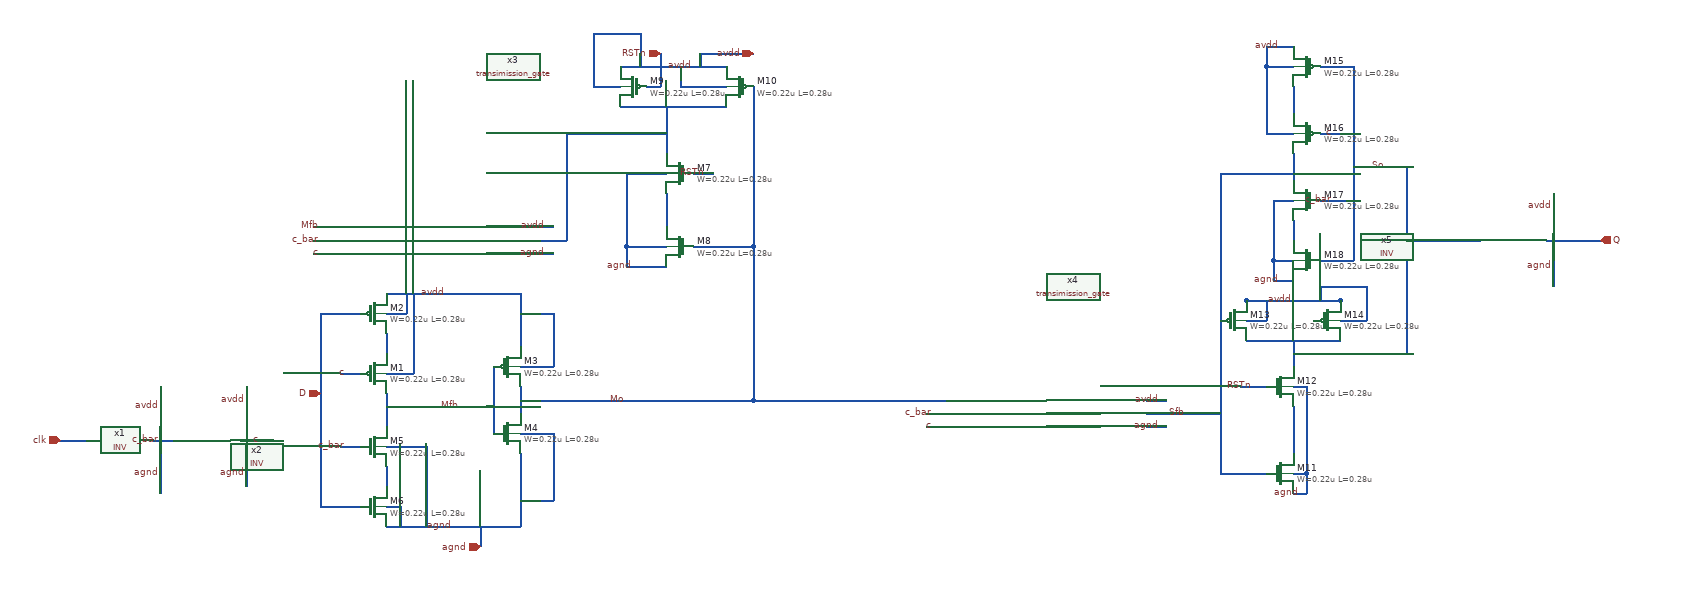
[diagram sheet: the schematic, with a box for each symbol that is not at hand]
v {xschem version=3.1.0 file_version=1.2
}
G {}
K {}
V {}
S {}
E {}
N 1270 -210 1320 -210 {
lab=c}
N 1000 -210 1040 -210 {
lab=clk}
N 1140 -210 1170 -210 {
lab=c_bar}
N 1490 -370 1490 -340 {
lab=#net1}
N 1490 -280 1490 -230 {
lab=Mfb}
N 1490 -170 1490 -140 {
lab=#net2}
N 1690 -290 1690 -250 {
lab=Mo}
N 1690 -190 1690 -80 {
lab=agnd}
N 1490 -80 1690 -80 {
lab=agnd}
N 1490 -430 1690 -430 {
lab=avdd}
N 1690 -430 1690 -350 {
lab=avdd}
N 1390 -400 1450 -400 {
lab=D}
N 1390 -400 1390 -110 {
lab=D}
N 1390 -110 1450 -110 {
lab=D}
N 1650 -320 1650 -220 {
lab=Mfb}
N 1490 -260 1650 -260 {
lab=Mfb}
N 1420 -310 1450 -310 {
lab=c}
N 1420 -200 1450 -200 {
lab=c_bar}
N 1490 -110 1510 -110 {
lab=agnd}
N 1510 -110 1510 -80 {
lab=agnd}
N 1490 -200 1550 -200 {
lab=agnd}
N 1550 -200 1550 -80 {
lab=agnd}
N 1690 -220 1740 -220 {
lab=agnd}
N 1740 -220 1740 -120 {
lab=agnd}
N 1690 -120 1740 -120 {
lab=agnd}
N 1690 -320 1740 -320 {
lab=avdd}
N 1740 -400 1740 -320 {
lab=avdd}
N 1690 -400 1740 -400 {
lab=avdd}
N 1380 -530 1410 -530 {
lab=Mfb}
N 1380 -510 1410 -510 {
lab=c_bar}
N 1380 -490 1410 -490 {
lab=c}
N 1710 -530 1740 -530 {
lab=avdd}
N 1710 -510 1740 -510 {
lab=#net3}
N 1710 -490 1740 -490 {
lab=agnd}
N 1910 -580 1910 -530 {
lab=#net4}
N 1850 -610 1910 -610 {
lab=agnd}
N 1850 -610 1850 -500 {
lab=agnd}
N 1850 -500 1910 -500 {
lab=agnd}
N 1850 -470 1910 -470 {
lab=agnd}
N 1850 -500 1850 -470 {
lab=agnd}
N 1840 -710 2000 -710 {
lab=#net3}
N 1910 -710 1910 -640 {
lab=#net3}
N 2040 -740 2040 -500 {
lab=Mo}
N 1950 -500 2040 -500 {
lab=Mo}
N 1950 -610 1980 -610 {
lab=RSTn}
N 1840 -770 2000 -770 {
lab=avdd}
N 1880 -740 1900 -740 {
lab=RSTn}
N 1900 -790 1900 -740 {
lab=RSTn}
N 1800 -740 1840 -740 {
lab=avdd}
N 1800 -820 1800 -740 {
lab=avdd}
N 1800 -820 1870 -820 {
lab=avdd}
N 1870 -820 1870 -770 {
lab=avdd}
N 1930 -740 2000 -740 {
lab=avdd}
N 1930 -770 1930 -740 {
lab=avdd}
N 1760 -670 1910 -670 {
lab=#net3}
N 1760 -670 1760 -510 {
lab=#net3}
N 1740 -510 1760 -510 {
lab=#net3}
N 2040 -500 2040 -290 {
lab=Mo}
N 1690 -270 2040 -270 {
lab=Mo}
N 2040 -290 2040 -270 {
lab=Mo}
N 2300 -270 2330 -270 {
lab=Mo}
N 2300 -250 2330 -250 {
lab=c_bar}
N 2300 -230 2330 -230 {
lab=c}
N 2630 -270 2660 -270 {
lab=avdd}
N 2630 -250 2660 -250 {
lab=Sfb}
N 2630 -230 2660 -230 {
lab=agnd}
N 2040 -270 2300 -270 {
lab=Mo}
N 2780 -420 2920 -420 {
lab=avdd}
N 2780 -360 2920 -360 {
lab=So}
N 2850 -360 2850 -320 {
lab=So}
N 2850 -260 2850 -190 {
lab=#net5}
N 2850 -290 2870 -290 {
lab=agnd}
N 2870 -290 2870 -160 {
lab=agnd}
N 2850 -160 2870 -160 {
lab=agnd}
N 2870 -160 2870 -130 {
lab=agnd}
N 2850 -130 2870 -130 {
lab=agnd}
N 2750 -160 2810 -160 {
lab=Sfb}
N 2740 -160 2750 -160 {
lab=Sfb}
N 2740 -390 2740 -160 {
lab=Sfb}
N 2660 -250 2740 -250 {
lab=Sfb}
N 2770 -290 2810 -290 {
lab=RSTn}
N 2920 -390 2960 -390 {
lab=avdd}
N 2960 -440 2960 -390 {
lab=avdd}
N 2890 -440 2960 -440 {
lab=avdd}
N 2890 -440 2890 -420 {
lab=avdd}
N 2780 -390 2810 -390 {
lab=avdd}
N 2810 -420 2810 -390 {
lab=avdd}
N 2820 -480 2850 -480 {
lab=agnd}
N 2820 -480 2820 -450 {
lab=agnd}
N 2820 -450 2850 -450 {
lab=agnd}
N 2820 -570 2850 -570 {
lab=agnd}
N 2820 -570 2820 -480 {
lab=agnd}
N 2850 -540 2850 -510 {
lab=#net6}
N 2850 -640 2850 -600 {
lab=Sfb}
N 2850 -740 2850 -700 {
lab=#net7}
N 2810 -670 2850 -670 {
lab=avdd}
N 2810 -770 2810 -670 {
lab=avdd}
N 2810 -770 2850 -770 {
lab=avdd}
N 2810 -800 2850 -800 {
lab=avdd}
N 2810 -800 2810 -770 {
lab=avdd}
N 2740 -610 2850 -610 {
lab=Sfb}
N 2740 -610 2740 -390 {
lab=Sfb}
N 2890 -770 2940 -770 {
lab=So}
N 2940 -770 2940 -480 {
lab=So}
N 2890 -480 2940 -480 {
lab=So}
N 2890 -670 2920 -670 {
lab=c}
N 2890 -570 2930 -570 {
lab=c_bar}
N 2850 -340 3020 -340 {
lab=So}
N 3020 -620 3020 -340 {
lab=So}
N 2940 -620 3020 -620 {
lab=So}
N 2780 -420 2920 -420 {
lab=avdd}
N 2780 -420 2920 -420 {
lab=avdd}
N 3020 -510 3130 -510 {
lab=So}
N 3230 -510 3310 -510 {
lab=Q}
N 1960 -790 2040 -790 {
lab=avdd}
N 1960 -790 1960 -770 {
lab=avdd}
N 1630 -80 1630 -50 {
lab=agnd}
N 1490 -400 1520 -400 {
lab=avdd}
N 1520 -430 1520 -400 {
lab=avdd}
N 1490 -310 1530 -310 {
lab=avdd}
N 1530 -430 1530 -310 {
lab=avdd}
N 3240 -580 3240 -530 {
lab=avdd}
N 3240 -490 3240 -440 {
lab=agnd}
N 1150 -290 1150 -230 {
lab=avdd}
N 1150 -190 1150 -130 {
lab=agnd}
N 1280 -290 1280 -230 {
lab=avdd}
N 1280 -190 1280 -140 {
lab=xxx}
C {INV.sym} 1100 -210 0 0 {name=x1}
C {INV.sym} 1230 -210 0 0 {name=x2}
C {pfet_03v3.sym} 1470 -310 0 0 {name=M1
L=0.28u
W=0.22u
nf=1
m=1
ad="'int((nf+1)/2) * W/nf * 0.18u'"
pd="'2*int((nf+1)/2) * (W/nf + 0.18u)'"
as="'int((nf+2)/2) * W/nf * 0.18u'"
ps="'2*int((nf+2)/2) * (W/nf + 0.18u)'"
nrd="'0.18u / W'" nrs="'0.18u / W'"
sa=0 sb=0 sd=0
model=pfet_03v3
spiceprefix=X
}
C {pfet_03v3.sym} 1470 -400 0 0 {name=M2
L=0.28u
W=0.22u
nf=1
m=1
ad="'int((nf+1)/2) * W/nf * 0.18u'"
pd="'2*int((nf+1)/2) * (W/nf + 0.18u)'"
as="'int((nf+2)/2) * W/nf * 0.18u'"
ps="'2*int((nf+2)/2) * (W/nf + 0.18u)'"
nrd="'0.18u / W'" nrs="'0.18u / W'"
sa=0 sb=0 sd=0
model=pfet_03v3
spiceprefix=X
}
C {pfet_03v3.sym} 1670 -320 0 0 {name=M3
L=0.28u
W=0.22u
nf=1
m=1
ad="'int((nf+1)/2) * W/nf * 0.18u'"
pd="'2*int((nf+1)/2) * (W/nf + 0.18u)'"
as="'int((nf+2)/2) * W/nf * 0.18u'"
ps="'2*int((nf+2)/2) * (W/nf + 0.18u)'"
nrd="'0.18u / W'" nrs="'0.18u / W'"
sa=0 sb=0 sd=0
model=pfet_03v3
spiceprefix=X
}
C {nfet_03v3.sym} 1670 -220 0 0 {name=M4
L=0.28u
W=0.22u
nf=1
m=1
ad="'int((nf+1)/2) * W/nf * 0.18u'"
pd="'2*int((nf+1)/2) * (W/nf + 0.18u)'"
as="'int((nf+2)/2) * W/nf * 0.18u'"
ps="'2*int((nf+2)/2) * (W/nf + 0.18u)'"
nrd="'0.18u / W'" nrs="'0.18u / W'"
sa=0 sb=0 sd=0
model=nfet_03v3
spiceprefix=X
}
C {nfet_03v3.sym} 1470 -200 0 0 {name=M5
L=0.28u
W=0.22u
nf=1
m=1
ad="'int((nf+1)/2) * W/nf * 0.18u'"
pd="'2*int((nf+1)/2) * (W/nf + 0.18u)'"
as="'int((nf+2)/2) * W/nf * 0.18u'"
ps="'2*int((nf+2)/2) * (W/nf + 0.18u)'"
nrd="'0.18u / W'" nrs="'0.18u / W'"
sa=0 sb=0 sd=0
model=nfet_03v3
spiceprefix=X
}
C {nfet_03v3.sym} 1470 -110 0 0 {name=M6
L=0.28u
W=0.22u
nf=1
m=1
ad="'int((nf+1)/2) * W/nf * 0.18u'"
pd="'2*int((nf+1)/2) * (W/nf + 0.18u)'"
as="'int((nf+2)/2) * W/nf * 0.18u'"
ps="'2*int((nf+2)/2) * (W/nf + 0.18u)'"
nrd="'0.18u / W'" nrs="'0.18u / W'"
sa=0 sb=0 sd=0
model=nfet_03v3
spiceprefix=X
}
C {lab_pin.sym} 1590 -80 0 0 {name=p1 sig_type=std_logic lab=agnd}
C {lab_pin.sym} 1580 -430 0 0 {name=p2 sig_type=std_logic lab=avdd}
C {lab_pin.sym} 1430 -310 0 0 {name=p3 sig_type=std_logic lab=c}
C {lab_pin.sym} 1430 -200 0 0 {name=p4 sig_type=std_logic lab=c_bar}
C {ipin.sym} 1000 -210 0 0 {name=p5 lab=clk}
C {lab_pin.sym} 1150 -210 0 0 {name=p6 sig_type=std_logic lab=c_bar}
C {lab_pin.sym} 1300 -210 0 0 {name=p7 sig_type=std_logic lab=c}
C {lab_pin.sym} 1600 -260 0 0 {name=p8 sig_type=std_logic lab=Mfb}
C {transimission_gate.sym} 1560 -510 0 0 {name=x3}
C {lab_pin.sym} 1730 -530 0 0 {name=p9 sig_type=std_logic lab=avdd}
C {lab_pin.sym} 1730 -490 0 0 {name=p10 sig_type=std_logic lab=agnd}
C {lab_pin.sym} 1390 -530 0 0 {name=p11 sig_type=std_logic lab=Mfb}
C {lab_pin.sym} 1390 -510 0 0 {name=p12 sig_type=std_logic lab=c_bar}
C {lab_pin.sym} 1390 -490 0 0 {name=p13 sig_type=std_logic lab=c}
C {nfet_03v3.sym} 1930 -610 0 1 {name=M7
L=0.28u
W=0.22u
nf=1
m=1
ad="'int((nf+1)/2) * W/nf * 0.18u'"
pd="'2*int((nf+1)/2) * (W/nf + 0.18u)'"
as="'int((nf+2)/2) * W/nf * 0.18u'"
ps="'2*int((nf+2)/2) * (W/nf + 0.18u)'"
nrd="'0.18u / W'" nrs="'0.18u / W'"
sa=0 sb=0 sd=0
model=nfet_03v3
spiceprefix=X
}
C {nfet_03v3.sym} 1930 -500 0 1 {name=M8
L=0.28u
W=0.22u
nf=1
m=1
ad="'int((nf+1)/2) * W/nf * 0.18u'"
pd="'2*int((nf+1)/2) * (W/nf + 0.18u)'"
as="'int((nf+2)/2) * W/nf * 0.18u'"
ps="'2*int((nf+2)/2) * (W/nf + 0.18u)'"
nrd="'0.18u / W'" nrs="'0.18u / W'"
sa=0 sb=0 sd=0
model=nfet_03v3
spiceprefix=X
}
C {pfet_03v3.sym} 1860 -740 0 1 {name=M9
L=0.28u
W=0.22u
nf=1
m=1
ad="'int((nf+1)/2) * W/nf * 0.18u'"
pd="'2*int((nf+1)/2) * (W/nf + 0.18u)'"
as="'int((nf+2)/2) * W/nf * 0.18u'"
ps="'2*int((nf+2)/2) * (W/nf + 0.18u)'"
nrd="'0.18u / W'" nrs="'0.18u / W'"
sa=0 sb=0 sd=0
model=pfet_03v3
spiceprefix=X
}
C {pfet_03v3.sym} 2020 -740 0 1 {name=M10
L=0.28u
W=0.22u
nf=1
m=1
ad="'int((nf+1)/2) * W/nf * 0.18u'"
pd="'2*int((nf+1)/2) * (W/nf + 0.18u)'"
as="'int((nf+2)/2) * W/nf * 0.18u'"
ps="'2*int((nf+2)/2) * (W/nf + 0.18u)'"
nrd="'0.18u / W'" nrs="'0.18u / W'"
sa=0 sb=0 sd=0
model=pfet_03v3
spiceprefix=X
}
C {lab_pin.sym} 1970 -610 0 0 {name=p14 sig_type=std_logic lab=RSTn}
C {ipin.sym} 1900 -790 0 0 {name=p15 lab=RSTn}
C {lab_pin.sym} 1950 -770 0 0 {name=p16 sig_type=std_logic lab=avdd}
C {lab_pin.sym} 1860 -470 0 0 {name=p17 sig_type=std_logic lab=agnd}
C {transimission_gate.sym} 2480 -250 0 0 {name=x4}
C {lab_pin.sym} 2650 -270 0 0 {name=p18 sig_type=std_logic lab=avdd}
C {lab_pin.sym} 2650 -230 0 0 {name=p19 sig_type=std_logic lab=agnd}
C {lab_pin.sym} 2310 -250 0 0 {name=p21 sig_type=std_logic lab=c_bar}
C {lab_pin.sym} 2310 -230 0 0 {name=p22 sig_type=std_logic lab=c}
C {lab_pin.sym} 1850 -270 0 0 {name=p20 sig_type=std_logic lab=Mo}
C {nfet_03v3.sym} 2830 -160 0 0 {name=M11
L=0.28u
W=0.22u
nf=1
m=1
ad="'int((nf+1)/2) * W/nf * 0.18u'"
pd="'2*int((nf+1)/2) * (W/nf + 0.18u)'"
as="'int((nf+2)/2) * W/nf * 0.18u'"
ps="'2*int((nf+2)/2) * (W/nf + 0.18u)'"
nrd="'0.18u / W'" nrs="'0.18u / W'"
sa=0 sb=0 sd=0
model=nfet_03v3
spiceprefix=X
}
C {nfet_03v3.sym} 2830 -290 0 0 {name=M12
L=0.28u
W=0.22u
nf=1
m=1
ad="'int((nf+1)/2) * W/nf * 0.18u'"
pd="'2*int((nf+1)/2) * (W/nf + 0.18u)'"
as="'int((nf+2)/2) * W/nf * 0.18u'"
ps="'2*int((nf+2)/2) * (W/nf + 0.18u)'"
nrd="'0.18u / W'" nrs="'0.18u / W'"
sa=0 sb=0 sd=0
model=nfet_03v3
spiceprefix=X
}
C {pfet_03v3.sym} 2760 -390 0 0 {name=M13
L=0.28u
W=0.22u
nf=1
m=1
ad="'int((nf+1)/2) * W/nf * 0.18u'"
pd="'2*int((nf+1)/2) * (W/nf + 0.18u)'"
as="'int((nf+2)/2) * W/nf * 0.18u'"
ps="'2*int((nf+2)/2) * (W/nf + 0.18u)'"
nrd="'0.18u / W'" nrs="'0.18u / W'"
sa=0 sb=0 sd=0
model=pfet_03v3
spiceprefix=X
}
C {pfet_03v3.sym} 2900 -390 0 0 {name=M14
L=0.28u
W=0.22u
nf=1
m=1
ad="'int((nf+1)/2) * W/nf * 0.18u'"
pd="'2*int((nf+1)/2) * (W/nf + 0.18u)'"
as="'int((nf+2)/2) * W/nf * 0.18u'"
ps="'2*int((nf+2)/2) * (W/nf + 0.18u)'"
nrd="'0.18u / W'" nrs="'0.18u / W'"
sa=0 sb=0 sd=0
model=pfet_03v3
spiceprefix=X
}
C {pfet_03v3.sym} 2870 -770 0 1 {name=M15
L=0.28u
W=0.22u
nf=1
m=1
ad="'int((nf+1)/2) * W/nf * 0.18u'"
pd="'2*int((nf+1)/2) * (W/nf + 0.18u)'"
as="'int((nf+2)/2) * W/nf * 0.18u'"
ps="'2*int((nf+2)/2) * (W/nf + 0.18u)'"
nrd="'0.18u / W'" nrs="'0.18u / W'"
sa=0 sb=0 sd=0
model=pfet_03v3
spiceprefix=X
}
C {pfet_03v3.sym} 2870 -670 0 1 {name=M16
L=0.28u
W=0.22u
nf=1
m=1
ad="'int((nf+1)/2) * W/nf * 0.18u'"
pd="'2*int((nf+1)/2) * (W/nf + 0.18u)'"
as="'int((nf+2)/2) * W/nf * 0.18u'"
ps="'2*int((nf+2)/2) * (W/nf + 0.18u)'"
nrd="'0.18u / W'" nrs="'0.18u / W'"
sa=0 sb=0 sd=0
model=pfet_03v3
spiceprefix=X
}
C {nfet_03v3.sym} 2870 -570 0 1 {name=M17
L=0.28u
W=0.22u
nf=1
m=1
ad="'int((nf+1)/2) * W/nf * 0.18u'"
pd="'2*int((nf+1)/2) * (W/nf + 0.18u)'"
as="'int((nf+2)/2) * W/nf * 0.18u'"
ps="'2*int((nf+2)/2) * (W/nf + 0.18u)'"
nrd="'0.18u / W'" nrs="'0.18u / W'"
sa=0 sb=0 sd=0
model=nfet_03v3
spiceprefix=X
}
C {nfet_03v3.sym} 2870 -480 0 1 {name=M18
L=0.28u
W=0.22u
nf=1
m=1
ad="'int((nf+1)/2) * W/nf * 0.18u'"
pd="'2*int((nf+1)/2) * (W/nf + 0.18u)'"
as="'int((nf+2)/2) * W/nf * 0.18u'"
ps="'2*int((nf+2)/2) * (W/nf + 0.18u)'"
nrd="'0.18u / W'" nrs="'0.18u / W'"
sa=0 sb=0 sd=0
model=nfet_03v3
spiceprefix=X
}
C {lab_pin.sym} 2790 -290 1 0 {name=p23 sig_type=std_logic lab=RSTn}
C {lab_pin.sym} 2910 -670 0 0 {name=p25 sig_type=std_logic lab=c}
C {lab_pin.sym} 2910 -570 0 0 {name=p26 sig_type=std_logic lab=c_bar}
C {lab_pin.sym} 2690 -250 0 0 {name=p27 sig_type=std_logic lab=Sfb}
C {lab_pin.sym} 2830 -800 0 0 {name=p28 sig_type=std_logic lab=avdd}
C {lab_pin.sym} 2830 -450 0 0 {name=p29 sig_type=std_logic lab=agnd}
C {lab_pin.sym} 2850 -420 0 0 {name=p24 sig_type=std_logic lab=avdd}
C {lab_pin.sym} 2860 -130 0 0 {name=p30 sig_type=std_logic lab=agnd}
C {lab_pin.sym} 2990 -620 0 0 {name=p31 sig_type=std_logic lab=So}
C {INV.sym} 3190 -510 0 0 {name=x5}
C {opin.sym} 3310 -510 0 0 {name=p32 lab=Q}
C {ipin.sym} 1390 -280 0 0 {name=p33 lab=D}
C {iopin.sym} 2040 -790 0 0 {name=p34 lab=avdd}
C {iopin.sym} 1630 -50 0 0 {name=p35 lab=agnd}
C {lab_pin.sym} 3240 -560 0 0 {name=p36 sig_type=std_logic lab=avdd}
C {lab_pin.sym} 3240 -470 0 0 {name=p37 sig_type=std_logic lab=agnd}
C {lab_pin.sym} 1150 -260 0 0 {name=p38 sig_type=std_logic lab=avdd}
C {lab_pin.sym} 1150 -160 0 0 {name=p39 sig_type=std_logic lab=agnd}
C {lab_pin.sym} 1280 -270 0 0 {name=p40 sig_type=std_logic lab=avdd}
C {lab_pin.sym} 1280 -160 0 0 {name=p41 sig_type=std_logic lab=agnd}
